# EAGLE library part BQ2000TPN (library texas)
CHARGE MANAGEMENT IC

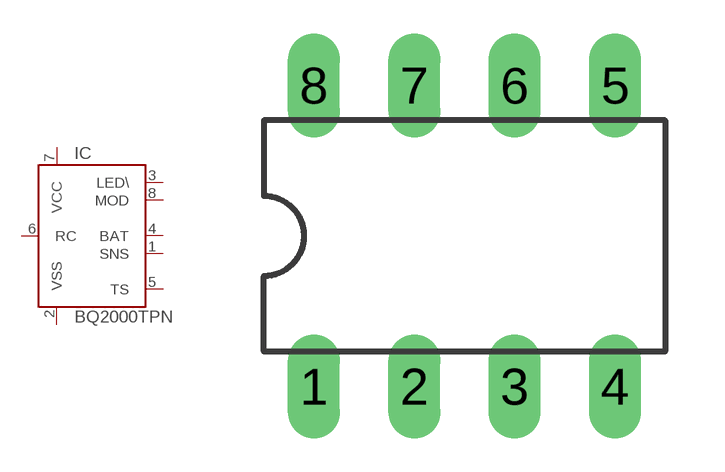
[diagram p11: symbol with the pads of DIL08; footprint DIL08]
Designator prefix IC

## BQ2000TPN  [DIL08]
1  SNS  in
2  VSS  pwr
3  LED\  out
4  BAT  in
5  TS  in
6  RC  in
7  VCC  in
8  MOD  out

## Footprint DIL08 (pad centres in mm)
Dual In Line Package
drill 0.813 long: 1 -3.81,-3.81; 2 -1.27,-3.81; 3 1.27,-3.81; 4 3.81,-3.81; 5 3.81,3.81; 6 1.27,3.81; 7 -1.27,3.81; 8 -3.81,3.81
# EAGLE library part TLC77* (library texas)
MICROPOWER SUPPLY VOLTAGE SUPERVISORS Source: www.ti.com/.. slvs087l.pdf

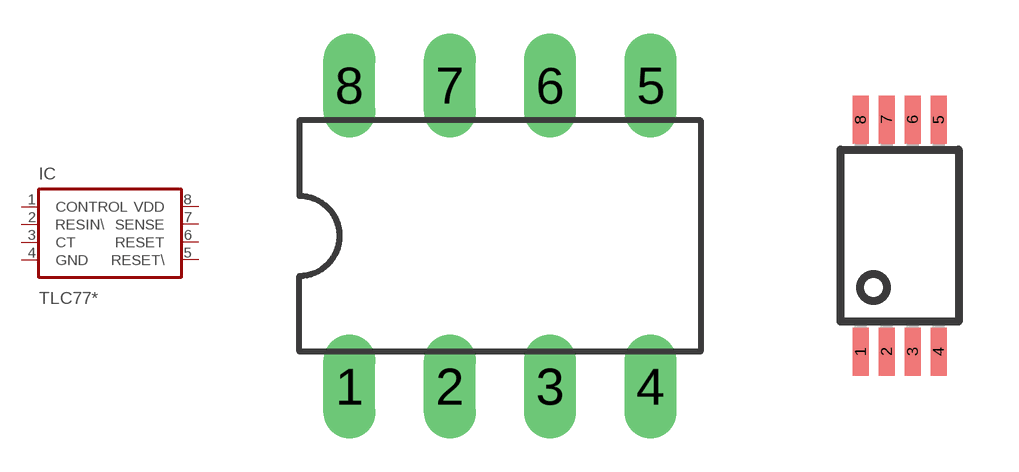
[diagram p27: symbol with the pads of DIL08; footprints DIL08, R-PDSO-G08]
Designator prefix IC

## TLC7701D, TLC7703D, TLC7705D, TLC7725D, TLC7733D  [DIL08]
1  CONTROL  in
2  RESIN\  in
3  CT  in
4  GND  pwr
5  RESET\  out
6  RESET  out
7  SENSE  in
8  VDD  pwr

## TLC7701PW, TLC7703PW, TLC7705PW, TLC7725PW, TLC7733PW  [R-PDSO-G08]
Pads as for DIL08

## TLC7701FK, TLC7703FK, TLC7705FK, TLC7725FK, TLC7733FK  [PLCC20]
1  CONTROL  in
5  RESIN\  in
7  CT  in
10  GND  pwr
12  RESET\  out
15  RESET  out
17  SENSE  in
20  VDD  pwr

## TLC7701P, TLC7703P, TLC7705P, TLC7725P, TLC7733P  [DIL08]
Pads as for DIL08

## Footprint DIL08 (pad centres in mm)
Dual In Line Package
drill 0.813 long: 1 -3.81,-3.81; 2 -1.27,-3.81; 3 1.27,-3.81; 4 3.81,-3.81; 5 3.81,3.81; 6 1.27,3.81; 7 -1.27,3.81; 8 -3.81,3.81

## Footprint R-PDSO-G08 (pad centres in mm)
PLASTIC SMALL-OUTLINE PACKAGE, SO 8 JEDEC MO-153 Source: www.ti.com/.. slvs087l.pdf
smd 0.4 x 1.2: 1 -0.975,-2.9; 2 -0.325,-2.9; 3 0.325,-2.9; 4 0.975,-2.9; 5 0.975,2.9; 6 0.325,2.9; 7 -0.325,2.9; 8 -0.975,2.9

## Footprint PLCC20 (pad centres in mm)
Plastic Leaded Chip Carrier
smd 0.6 x 2.2: 1 0,4.3; 2 -1.27,4.3; 3 -2.54,4.3; 9 -2.54,-4.3; 10 -1.27,-4.3; 11 0,-4.3; 12 1.27,-4.3; 13 2.54,-4.3; 19 2.54,4.3; 20 1.27,4.3
smd 2.2 x 0.6: 4 -4.3,2.54; 5 -4.3,1.27; 6 -4.3,0; 7 -4.3,-1.27; 8 -4.3,-2.54; 14 4.3,-2.54; 15 4.3,-1.27; 16 4.3,0; 17 4.3,1.27; 18 4.3,2.54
